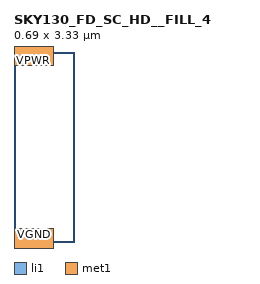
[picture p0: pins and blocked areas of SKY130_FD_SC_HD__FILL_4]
MACRO SKY130_FD_SC_HD__FILL_4
 CLASS CORE ;
 FOREIGN SKY130_FD_SC_HD__FILL_4 0 0 ;
 SIZE 0.6900000000000001 BY 3.33 ;
 ORIGIN 0 0 ;
 SYMMETRY X Y R90 ;
 SITE unit ;
  PIN VPWR
   DIRECTION INOUT ;
   USE POWER ;
   SHAPE ABUTMENT ;
    PORT
     CLASS CORE ;
       LAYER li1 ;
        RECT 0.00000000 3.09000000 0.69000000 3.57000000 ;
       LAYER met1 ;
        RECT 0.00000000 3.09000000 0.69000000 3.57000000 ;
    END
  END VPWR

  PIN VGND
   DIRECTION INOUT ;
   USE POWER ;
   SHAPE ABUTMENT ;
    PORT
     CLASS CORE ;
       LAYER li1 ;
        RECT 0.00000000 -0.24000000 0.69000000 0.24000000 ;
       LAYER met1 ;
        RECT 0.00000000 -0.24000000 0.69000000 0.24000000 ;
    END
  END VGND

 OBS
    LAYER polycont ;


    LAYER pdiffc ;


    LAYER ndiffc ;


    LAYER li1 ;
     RECT 0.00000000 3.09000000 0.69000000 3.57000000 ;
     RECT 0.00000000 -0.24000000 0.69000000 0.24000000 ;

    LAYER viali ;
     RECT 0.14500000 3.24500000 0.31500000 3.41500000 ;
     RECT 0.14500000 -0.08500000 0.31500000 0.08500000 ;

    LAYER met1 ;
     RECT 0.00000000 3.09000000 0.69000000 3.57000000 ;
     RECT 0.00000000 -0.24000000 0.69000000 0.24000000 ;

    LAYER via ;


    LAYER met2 ;


    LAYER via2 ;


    LAYER met3 ;


 END
END SKY130_FD_SC_HD__FILL_4
